# Placeholder macro written by tools/chip_assembly/macros.py
# kind: tile; as ot_pdie_tile_io without die-level pins: an M1-M7 blockage
VERSION 5.7 ;
BUSBITCHARS "[]" ;
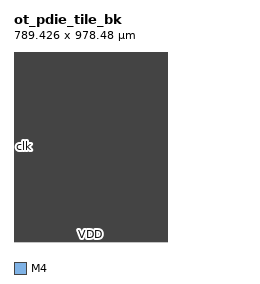
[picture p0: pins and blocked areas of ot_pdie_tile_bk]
MACRO ot_pdie_tile_bk
  FOREIGN ot_pdie_tile_bk 0 0 ;
  SYMMETRY X Y R90 ;
  SIZE 789.426 BY 978.480 ;
  CLASS BLOCK ;
  PIN clk
    DIRECTION INPUT ;
    USE SIGNAL ;
    SHAPE ABUTMENT ;
    PORT
      LAYER M4 ;
      RECT 0.000 489.264 0.192 489.288 ;
    END
  END clk
  PIN VSS
    DIRECTION INOUT ;
    USE GROUND ;
    PORT
      LAYER M4 ;
      RECT 0.492 1.200 788.934 1.296 ;
      RECT 0.492 3.600 788.934 3.696 ;
      RECT 0.492 6.000 788.934 6.096 ;
      RECT 0.492 8.400 788.934 8.496 ;
      RECT 0.492 10.800 788.934 10.896 ;
      RECT 0.492 13.200 788.934 13.296 ;
      RECT 0.492 15.600 788.934 15.696 ;
      RECT 0.492 18.000 788.934 18.096 ;
      RECT 0.492 20.400 788.934 20.496 ;
      RECT 0.492 22.800 788.934 22.896 ;
      RECT 0.492 25.200 788.934 25.296 ;
      RECT 0.492 27.600 788.934 27.696 ;
      RECT 0.492 30.000 788.934 30.096 ;
      RECT 0.492 32.400 788.934 32.496 ;
      RECT 0.492 34.800 788.934 34.896 ;
      RECT 0.492 37.200 788.934 37.296 ;
      RECT 0.492 39.600 788.934 39.696 ;
      RECT 0.492 42.000 788.934 42.096 ;
      RECT 0.492 44.400 788.934 44.496 ;
      RECT 0.492 46.800 788.934 46.896 ;
      RECT 0.492 49.200 788.934 49.296 ;
      RECT 0.492 51.600 788.934 51.696 ;
      RECT 0.492 54.000 788.934 54.096 ;
      RECT 0.492 56.400 788.934 56.496 ;
      RECT 0.492 58.800 788.934 58.896 ;
      RECT 0.492 61.200 788.934 61.296 ;
      RECT 0.492 63.600 788.934 63.696 ;
      RECT 0.492 66.000 788.934 66.096 ;
      RECT 0.492 68.400 788.934 68.496 ;
      RECT 0.492 70.800 788.934 70.896 ;
      RECT 0.492 73.200 788.934 73.296 ;
      RECT 0.492 75.600 788.934 75.696 ;
      RECT 0.492 78.000 788.934 78.096 ;
      RECT 0.492 80.400 788.934 80.496 ;
      RECT 0.492 82.800 788.934 82.896 ;
      RECT 0.492 85.200 788.934 85.296 ;
      RECT 0.492 87.600 788.934 87.696 ;
      RECT 0.492 90.000 788.934 90.096 ;
      RECT 0.492 92.400 788.934 92.496 ;
      RECT 0.492 94.800 788.934 94.896 ;
      RECT 0.492 97.200 788.934 97.296 ;
      RECT 0.492 99.600 788.934 99.696 ;
      RECT 0.492 102.000 788.934 102.096 ;
      RECT 0.492 104.400 788.934 104.496 ;
      RECT 0.492 106.800 788.934 106.896 ;
      RECT 0.492 109.200 788.934 109.296 ;
      RECT 0.492 111.600 788.934 111.696 ;
      RECT 0.492 114.000 788.934 114.096 ;
      RECT 0.492 116.400 788.934 116.496 ;
      RECT 0.492 118.800 788.934 118.896 ;
      RECT 0.492 121.200 788.934 121.296 ;
      RECT 0.492 123.600 788.934 123.696 ;
      RECT 0.492 126.000 788.934 126.096 ;
      RECT 0.492 128.400 788.934 128.496 ;
      RECT 0.492 130.800 788.934 130.896 ;
      RECT 0.492 133.200 788.934 133.296 ;
      RECT 0.492 135.600 788.934 135.696 ;
      RECT 0.492 138.000 788.934 138.096 ;
      RECT 0.492 140.400 788.934 140.496 ;
      RECT 0.492 142.800 788.934 142.896 ;
      RECT 0.492 145.200 788.934 145.296 ;
      RECT 0.492 147.600 788.934 147.696 ;
      RECT 0.492 150.000 788.934 150.096 ;
      RECT 0.492 152.400 788.934 152.496 ;
      RECT 0.492 154.800 788.934 154.896 ;
      RECT 0.492 157.200 788.934 157.296 ;
      RECT 0.492 159.600 788.934 159.696 ;
      RECT 0.492 162.000 788.934 162.096 ;
      RECT 0.492 164.400 788.934 164.496 ;
      RECT 0.492 166.800 788.934 166.896 ;
      RECT 0.492 169.200 788.934 169.296 ;
      RECT 0.492 171.600 788.934 171.696 ;
      RECT 0.492 174.000 788.934 174.096 ;
      RECT 0.492 176.400 788.934 176.496 ;
      RECT 0.492 178.800 788.934 178.896 ;
      RECT 0.492 181.200 788.934 181.296 ;
      RECT 0.492 183.600 788.934 183.696 ;
      RECT 0.492 186.000 788.934 186.096 ;
      RECT 0.492 188.400 788.934 188.496 ;
      RECT 0.492 190.800 788.934 190.896 ;
      RECT 0.492 193.200 788.934 193.296 ;
      RECT 0.492 195.600 788.934 195.696 ;
      RECT 0.492 198.000 788.934 198.096 ;
      RECT 0.492 200.400 788.934 200.496 ;
      RECT 0.492 202.800 788.934 202.896 ;
      RECT 0.492 205.200 788.934 205.296 ;
      RECT 0.492 207.600 788.934 207.696 ;
      RECT 0.492 210.000 788.934 210.096 ;
      RECT 0.492 212.400 788.934 212.496 ;
      RECT 0.492 214.800 788.934 214.896 ;
      RECT 0.492 217.200 788.934 217.296 ;
      RECT 0.492 219.600 788.934 219.696 ;
      RECT 0.492 222.000 788.934 222.096 ;
      RECT 0.492 224.400 788.934 224.496 ;
      RECT 0.492 226.800 788.934 226.896 ;
      RECT 0.492 229.200 788.934 229.296 ;
      RECT 0.492 231.600 788.934 231.696 ;
      RECT 0.492 234.000 788.934 234.096 ;
      RECT 0.492 236.400 788.934 236.496 ;
      RECT 0.492 238.800 788.934 238.896 ;
      RECT 0.492 241.200 788.934 241.296 ;
      RECT 0.492 243.600 788.934 243.696 ;
      RECT 0.492 246.000 788.934 246.096 ;
      RECT 0.492 248.400 788.934 248.496 ;
      RECT 0.492 250.800 788.934 250.896 ;
      RECT 0.492 253.200 788.934 253.296 ;
      RECT 0.492 255.600 788.934 255.696 ;
      RECT 0.492 258.000 788.934 258.096 ;
      RECT 0.492 260.400 788.934 260.496 ;
      RECT 0.492 262.800 788.934 262.896 ;
      RECT 0.492 265.200 788.934 265.296 ;
      RECT 0.492 267.600 788.934 267.696 ;
      RECT 0.492 270.000 788.934 270.096 ;
      RECT 0.492 272.400 788.934 272.496 ;
      RECT 0.492 274.800 788.934 274.896 ;
      RECT 0.492 277.200 788.934 277.296 ;
      RECT 0.492 279.600 788.934 279.696 ;
      RECT 0.492 282.000 788.934 282.096 ;
      RECT 0.492 284.400 788.934 284.496 ;
      RECT 0.492 286.800 788.934 286.896 ;
      RECT 0.492 289.200 788.934 289.296 ;
      RECT 0.492 291.600 788.934 291.696 ;
      RECT 0.492 294.000 788.934 294.096 ;
      RECT 0.492 296.400 788.934 296.496 ;
      RECT 0.492 298.800 788.934 298.896 ;
      RECT 0.492 301.200 788.934 301.296 ;
      RECT 0.492 303.600 788.934 303.696 ;
      RECT 0.492 306.000 788.934 306.096 ;
      RECT 0.492 308.400 788.934 308.496 ;
      RECT 0.492 310.800 788.934 310.896 ;
      RECT 0.492 313.200 788.934 313.296 ;
      RECT 0.492 315.600 788.934 315.696 ;
      RECT 0.492 318.000 788.934 318.096 ;
      RECT 0.492 320.400 788.934 320.496 ;
      RECT 0.492 322.800 788.934 322.896 ;
      RECT 0.492 325.200 788.934 325.296 ;
      RECT 0.492 327.600 788.934 327.696 ;
      RECT 0.492 330.000 788.934 330.096 ;
      RECT 0.492 332.400 788.934 332.496 ;
      RECT 0.492 334.800 788.934 334.896 ;
      RECT 0.492 337.200 788.934 337.296 ;
      RECT 0.492 339.600 788.934 339.696 ;
      RECT 0.492 342.000 788.934 342.096 ;
      RECT 0.492 344.400 788.934 344.496 ;
      RECT 0.492 346.800 788.934 346.896 ;
      RECT 0.492 349.200 788.934 349.296 ;
      RECT 0.492 351.600 788.934 351.696 ;
      RECT 0.492 354.000 788.934 354.096 ;
      RECT 0.492 356.400 788.934 356.496 ;
      RECT 0.492 358.800 788.934 358.896 ;
      RECT 0.492 361.200 788.934 361.296 ;
      RECT 0.492 363.600 788.934 363.696 ;
      RECT 0.492 366.000 788.934 366.096 ;
      RECT 0.492 368.400 788.934 368.496 ;
      RECT 0.492 370.800 788.934 370.896 ;
      RECT 0.492 373.200 788.934 373.296 ;
      RECT 0.492 375.600 788.934 375.696 ;
      RECT 0.492 378.000 788.934 378.096 ;
      RECT 0.492 380.400 788.934 380.496 ;
      RECT 0.492 382.800 788.934 382.896 ;
      RECT 0.492 385.200 788.934 385.296 ;
      RECT 0.492 387.600 788.934 387.696 ;
      RECT 0.492 390.000 788.934 390.096 ;
      RECT 0.492 392.400 788.934 392.496 ;
      RECT 0.492 394.800 788.934 394.896 ;
      RECT 0.492 397.200 788.934 397.296 ;
      RECT 0.492 399.600 788.934 399.696 ;
      RECT 0.492 402.000 788.934 402.096 ;
      RECT 0.492 404.400 788.934 404.496 ;
      RECT 0.492 406.800 788.934 406.896 ;
      RECT 0.492 409.200 788.934 409.296 ;
      RECT 0.492 411.600 788.934 411.696 ;
      RECT 0.492 414.000 788.934 414.096 ;
      RECT 0.492 416.400 788.934 416.496 ;
      RECT 0.492 418.800 788.934 418.896 ;
      RECT 0.492 421.200 788.934 421.296 ;
      RECT 0.492 423.600 788.934 423.696 ;
      RECT 0.492 426.000 788.934 426.096 ;
      RECT 0.492 428.400 788.934 428.496 ;
      RECT 0.492 430.800 788.934 430.896 ;
      RECT 0.492 433.200 788.934 433.296 ;
      RECT 0.492 435.600 788.934 435.696 ;
      RECT 0.492 438.000 788.934 438.096 ;
      RECT 0.492 440.400 788.934 440.496 ;
      RECT 0.492 442.800 788.934 442.896 ;
      RECT 0.492 445.200 788.934 445.296 ;
      RECT 0.492 447.600 788.934 447.696 ;
      RECT 0.492 450.000 788.934 450.096 ;
      RECT 0.492 452.400 788.934 452.496 ;
      RECT 0.492 454.800 788.934 454.896 ;
      RECT 0.492 457.200 788.934 457.296 ;
      RECT 0.492 459.600 788.934 459.696 ;
      RECT 0.492 462.000 788.934 462.096 ;
      RECT 0.492 464.400 788.934 464.496 ;
      RECT 0.492 466.800 788.934 466.896 ;
      RECT 0.492 469.200 788.934 469.296 ;
      RECT 0.492 471.600 788.934 471.696 ;
      RECT 0.492 474.000 788.934 474.096 ;
      RECT 0.492 476.400 788.934 476.496 ;
      RECT 0.492 478.800 788.934 478.896 ;
      RECT 0.492 481.200 788.934 481.296 ;
      RECT 0.492 483.600 788.934 483.696 ;
      RECT 0.492 486.000 788.934 486.096 ;
      RECT 0.492 488.400 788.934 488.496 ;
      RECT 0.492 490.800 788.934 490.896 ;
      RECT 0.492 493.200 788.934 493.296 ;
      RECT 0.492 495.600 788.934 495.696 ;
      RECT 0.492 498.000 788.934 498.096 ;
      RECT 0.492 500.400 788.934 500.496 ;
      RECT 0.492 502.800 788.934 502.896 ;
      RECT 0.492 505.200 788.934 505.296 ;
      RECT 0.492 507.600 788.934 507.696 ;
      RECT 0.492 510.000 788.934 510.096 ;
      RECT 0.492 512.400 788.934 512.496 ;
      RECT 0.492 514.800 788.934 514.896 ;
      RECT 0.492 517.200 788.934 517.296 ;
      RECT 0.492 519.600 788.934 519.696 ;
      RECT 0.492 522.000 788.934 522.096 ;
      RECT 0.492 524.400 788.934 524.496 ;
      RECT 0.492 526.800 788.934 526.896 ;
      RECT 0.492 529.200 788.934 529.296 ;
      RECT 0.492 531.600 788.934 531.696 ;
      RECT 0.492 534.000 788.934 534.096 ;
      RECT 0.492 536.400 788.934 536.496 ;
      RECT 0.492 538.800 788.934 538.896 ;
      RECT 0.492 541.200 788.934 541.296 ;
      RECT 0.492 543.600 788.934 543.696 ;
      RECT 0.492 546.000 788.934 546.096 ;
      RECT 0.492 548.400 788.934 548.496 ;
      RECT 0.492 550.800 788.934 550.896 ;
      RECT 0.492 553.200 788.934 553.296 ;
      RECT 0.492 555.600 788.934 555.696 ;
      RECT 0.492 558.000 788.934 558.096 ;
      RECT 0.492 560.400 788.934 560.496 ;
      RECT 0.492 562.800 788.934 562.896 ;
      RECT 0.492 565.200 788.934 565.296 ;
      RECT 0.492 567.600 788.934 567.696 ;
      RECT 0.492 570.000 788.934 570.096 ;
      RECT 0.492 572.400 788.934 572.496 ;
      RECT 0.492 574.800 788.934 574.896 ;
      RECT 0.492 577.200 788.934 577.296 ;
      RECT 0.492 579.600 788.934 579.696 ;
      RECT 0.492 582.000 788.934 582.096 ;
      RECT 0.492 584.400 788.934 584.496 ;
      RECT 0.492 586.800 788.934 586.896 ;
      RECT 0.492 589.200 788.934 589.296 ;
      RECT 0.492 591.600 788.934 591.696 ;
      RECT 0.492 594.000 788.934 594.096 ;
      RECT 0.492 596.400 788.934 596.496 ;
      RECT 0.492 598.800 788.934 598.896 ;
      RECT 0.492 601.200 788.934 601.296 ;
      RECT 0.492 603.600 788.934 603.696 ;
      RECT 0.492 606.000 788.934 606.096 ;
      RECT 0.492 608.400 788.934 608.496 ;
      RECT 0.492 610.800 788.934 610.896 ;
      RECT 0.492 613.200 788.934 613.296 ;
      RECT 0.492 615.600 788.934 615.696 ;
      RECT 0.492 618.000 788.934 618.096 ;
      RECT 0.492 620.400 788.934 620.496 ;
      RECT 0.492 622.800 788.934 622.896 ;
      RECT 0.492 625.200 788.934 625.296 ;
      RECT 0.492 627.600 788.934 627.696 ;
      RECT 0.492 630.000 788.934 630.096 ;
      RECT 0.492 632.400 788.934 632.496 ;
      RECT 0.492 634.800 788.934 634.896 ;
      RECT 0.492 637.200 788.934 637.296 ;
      RECT 0.492 639.600 788.934 639.696 ;
      RECT 0.492 642.000 788.934 642.096 ;
      RECT 0.492 644.400 788.934 644.496 ;
      RECT 0.492 646.800 788.934 646.896 ;
      RECT 0.492 649.200 788.934 649.296 ;
      RECT 0.492 651.600 788.934 651.696 ;
      RECT 0.492 654.000 788.934 654.096 ;
      RECT 0.492 656.400 788.934 656.496 ;
      RECT 0.492 658.800 788.934 658.896 ;
      RECT 0.492 661.200 788.934 661.296 ;
      RECT 0.492 663.600 788.934 663.696 ;
      RECT 0.492 666.000 788.934 666.096 ;
      RECT 0.492 668.400 788.934 668.496 ;
      RECT 0.492 670.800 788.934 670.896 ;
      RECT 0.492 673.200 788.934 673.296 ;
      RECT 0.492 675.600 788.934 675.696 ;
      RECT 0.492 678.000 788.934 678.096 ;
      RECT 0.492 680.400 788.934 680.496 ;
      RECT 0.492 682.800 788.934 682.896 ;
      RECT 0.492 685.200 788.934 685.296 ;
      RECT 0.492 687.600 788.934 687.696 ;
      RECT 0.492 690.000 788.934 690.096 ;
      RECT 0.492 692.400 788.934 692.496 ;
      RECT 0.492 694.800 788.934 694.896 ;
      RECT 0.492 697.200 788.934 697.296 ;
      RECT 0.492 699.600 788.934 699.696 ;
      RECT 0.492 702.000 788.934 702.096 ;
      RECT 0.492 704.400 788.934 704.496 ;
      RECT 0.492 706.800 788.934 706.896 ;
      RECT 0.492 709.200 788.934 709.296 ;
      RECT 0.492 711.600 788.934 711.696 ;
      RECT 0.492 714.000 788.934 714.096 ;
      RECT 0.492 716.400 788.934 716.496 ;
      RECT 0.492 718.800 788.934 718.896 ;
      RECT 0.492 721.200 788.934 721.296 ;
      RECT 0.492 723.600 788.934 723.696 ;
      RECT 0.492 726.000 788.934 726.096 ;
      RECT 0.492 728.400 788.934 728.496 ;
      RECT 0.492 730.800 788.934 730.896 ;
      RECT 0.492 733.200 788.934 733.296 ;
      RECT 0.492 735.600 788.934 735.696 ;
      RECT 0.492 738.000 788.934 738.096 ;
      RECT 0.492 740.400 788.934 740.496 ;
      RECT 0.492 742.800 788.934 742.896 ;
      RECT 0.492 745.200 788.934 745.296 ;
      RECT 0.492 747.600 788.934 747.696 ;
      RECT 0.492 750.000 788.934 750.096 ;
      RECT 0.492 752.400 788.934 752.496 ;
      RECT 0.492 754.800 788.934 754.896 ;
      RECT 0.492 757.200 788.934 757.296 ;
      RECT 0.492 759.600 788.934 759.696 ;
      RECT 0.492 762.000 788.934 762.096 ;
      RECT 0.492 764.400 788.934 764.496 ;
      RECT 0.492 766.800 788.934 766.896 ;
      RECT 0.492 769.200 788.934 769.296 ;
      RECT 0.492 771.600 788.934 771.696 ;
      RECT 0.492 774.000 788.934 774.096 ;
      RECT 0.492 776.400 788.934 776.496 ;
      RECT 0.492 778.800 788.934 778.896 ;
      RECT 0.492 781.200 788.934 781.296 ;
      RECT 0.492 783.600 788.934 783.696 ;
      RECT 0.492 786.000 788.934 786.096 ;
      RECT 0.492 788.400 788.934 788.496 ;
      RECT 0.492 790.800 788.934 790.896 ;
      RECT 0.492 793.200 788.934 793.296 ;
      RECT 0.492 795.600 788.934 795.696 ;
      RECT 0.492 798.000 788.934 798.096 ;
      RECT 0.492 800.400 788.934 800.496 ;
      RECT 0.492 802.800 788.934 802.896 ;
      RECT 0.492 805.200 788.934 805.296 ;
      RECT 0.492 807.600 788.934 807.696 ;
      RECT 0.492 810.000 788.934 810.096 ;
      RECT 0.492 812.400 788.934 812.496 ;
      RECT 0.492 814.800 788.934 814.896 ;
      RECT 0.492 817.200 788.934 817.296 ;
      RECT 0.492 819.600 788.934 819.696 ;
      RECT 0.492 822.000 788.934 822.096 ;
      RECT 0.492 824.400 788.934 824.496 ;
      RECT 0.492 826.800 788.934 826.896 ;
      RECT 0.492 829.200 788.934 829.296 ;
      RECT 0.492 831.600 788.934 831.696 ;
      RECT 0.492 834.000 788.934 834.096 ;
      RECT 0.492 836.400 788.934 836.496 ;
      RECT 0.492 838.800 788.934 838.896 ;
      RECT 0.492 841.200 788.934 841.296 ;
      RECT 0.492 843.600 788.934 843.696 ;
      RECT 0.492 846.000 788.934 846.096 ;
      RECT 0.492 848.400 788.934 848.496 ;
      RECT 0.492 850.800 788.934 850.896 ;
      RECT 0.492 853.200 788.934 853.296 ;
      RECT 0.492 855.600 788.934 855.696 ;
      RECT 0.492 858.000 788.934 858.096 ;
      RECT 0.492 860.400 788.934 860.496 ;
      RECT 0.492 862.800 788.934 862.896 ;
      RECT 0.492 865.200 788.934 865.296 ;
      RECT 0.492 867.600 788.934 867.696 ;
      RECT 0.492 870.000 788.934 870.096 ;
      RECT 0.492 872.400 788.934 872.496 ;
      RECT 0.492 874.800 788.934 874.896 ;
      RECT 0.492 877.200 788.934 877.296 ;
      RECT 0.492 879.600 788.934 879.696 ;
      RECT 0.492 882.000 788.934 882.096 ;
      RECT 0.492 884.400 788.934 884.496 ;
      RECT 0.492 886.800 788.934 886.896 ;
      RECT 0.492 889.200 788.934 889.296 ;
      RECT 0.492 891.600 788.934 891.696 ;
      RECT 0.492 894.000 788.934 894.096 ;
      RECT 0.492 896.400 788.934 896.496 ;
      RECT 0.492 898.800 788.934 898.896 ;
      RECT 0.492 901.200 788.934 901.296 ;
      RECT 0.492 903.600 788.934 903.696 ;
      RECT 0.492 906.000 788.934 906.096 ;
      RECT 0.492 908.400 788.934 908.496 ;
      RECT 0.492 910.800 788.934 910.896 ;
      RECT 0.492 913.200 788.934 913.296 ;
      RECT 0.492 915.600 788.934 915.696 ;
      RECT 0.492 918.000 788.934 918.096 ;
      RECT 0.492 920.400 788.934 920.496 ;
      RECT 0.492 922.800 788.934 922.896 ;
      RECT 0.492 925.200 788.934 925.296 ;
      RECT 0.492 927.600 788.934 927.696 ;
      RECT 0.492 930.000 788.934 930.096 ;
      RECT 0.492 932.400 788.934 932.496 ;
      RECT 0.492 934.800 788.934 934.896 ;
      RECT 0.492 937.200 788.934 937.296 ;
      RECT 0.492 939.600 788.934 939.696 ;
      RECT 0.492 942.000 788.934 942.096 ;
      RECT 0.492 944.400 788.934 944.496 ;
      RECT 0.492 946.800 788.934 946.896 ;
      RECT 0.492 949.200 788.934 949.296 ;
      RECT 0.492 951.600 788.934 951.696 ;
      RECT 0.492 954.000 788.934 954.096 ;
      RECT 0.492 956.400 788.934 956.496 ;
      RECT 0.492 958.800 788.934 958.896 ;
      RECT 0.492 961.200 788.934 961.296 ;
      RECT 0.492 963.600 788.934 963.696 ;
      RECT 0.492 966.000 788.934 966.096 ;
      RECT 0.492 968.400 788.934 968.496 ;
      RECT 0.492 970.800 788.934 970.896 ;
      RECT 0.492 973.200 788.934 973.296 ;
      RECT 0.492 975.600 788.934 975.696 ;
    END
  END VSS
  PIN VDD
    DIRECTION INOUT ;
    USE POWER ;
    PORT
      LAYER M4 ;
      RECT 0.492 2.400 788.934 2.496 ;
      RECT 0.492 4.800 788.934 4.896 ;
      RECT 0.492 7.200 788.934 7.296 ;
      RECT 0.492 9.600 788.934 9.696 ;
      RECT 0.492 12.000 788.934 12.096 ;
      RECT 0.492 14.400 788.934 14.496 ;
      RECT 0.492 16.800 788.934 16.896 ;
      RECT 0.492 19.200 788.934 19.296 ;
      RECT 0.492 21.600 788.934 21.696 ;
      RECT 0.492 24.000 788.934 24.096 ;
      RECT 0.492 26.400 788.934 26.496 ;
      RECT 0.492 28.800 788.934 28.896 ;
      RECT 0.492 31.200 788.934 31.296 ;
      RECT 0.492 33.600 788.934 33.696 ;
      RECT 0.492 36.000 788.934 36.096 ;
      RECT 0.492 38.400 788.934 38.496 ;
      RECT 0.492 40.800 788.934 40.896 ;
      RECT 0.492 43.200 788.934 43.296 ;
      RECT 0.492 45.600 788.934 45.696 ;
      RECT 0.492 48.000 788.934 48.096 ;
      RECT 0.492 50.400 788.934 50.496 ;
      RECT 0.492 52.800 788.934 52.896 ;
      RECT 0.492 55.200 788.934 55.296 ;
      RECT 0.492 57.600 788.934 57.696 ;
      RECT 0.492 60.000 788.934 60.096 ;
      RECT 0.492 62.400 788.934 62.496 ;
      RECT 0.492 64.800 788.934 64.896 ;
      RECT 0.492 67.200 788.934 67.296 ;
      RECT 0.492 69.600 788.934 69.696 ;
      RECT 0.492 72.000 788.934 72.096 ;
      RECT 0.492 74.400 788.934 74.496 ;
      RECT 0.492 76.800 788.934 76.896 ;
      RECT 0.492 79.200 788.934 79.296 ;
      RECT 0.492 81.600 788.934 81.696 ;
      RECT 0.492 84.000 788.934 84.096 ;
      RECT 0.492 86.400 788.934 86.496 ;
      RECT 0.492 88.800 788.934 88.896 ;
      RECT 0.492 91.200 788.934 91.296 ;
      RECT 0.492 93.600 788.934 93.696 ;
      RECT 0.492 96.000 788.934 96.096 ;
      RECT 0.492 98.400 788.934 98.496 ;
      RECT 0.492 100.800 788.934 100.896 ;
      RECT 0.492 103.200 788.934 103.296 ;
      RECT 0.492 105.600 788.934 105.696 ;
      RECT 0.492 108.000 788.934 108.096 ;
      RECT 0.492 110.400 788.934 110.496 ;
      RECT 0.492 112.800 788.934 112.896 ;
      RECT 0.492 115.200 788.934 115.296 ;
      RECT 0.492 117.600 788.934 117.696 ;
      RECT 0.492 120.000 788.934 120.096 ;
      RECT 0.492 122.400 788.934 122.496 ;
      RECT 0.492 124.800 788.934 124.896 ;
      RECT 0.492 127.200 788.934 127.296 ;
      RECT 0.492 129.600 788.934 129.696 ;
      RECT 0.492 132.000 788.934 132.096 ;
      RECT 0.492 134.400 788.934 134.496 ;
      RECT 0.492 136.800 788.934 136.896 ;
      RECT 0.492 139.200 788.934 139.296 ;
      RECT 0.492 141.600 788.934 141.696 ;
      RECT 0.492 144.000 788.934 144.096 ;
      RECT 0.492 146.400 788.934 146.496 ;
      RECT 0.492 148.800 788.934 148.896 ;
      RECT 0.492 151.200 788.934 151.296 ;
      RECT 0.492 153.600 788.934 153.696 ;
      RECT 0.492 156.000 788.934 156.096 ;
      RECT 0.492 158.400 788.934 158.496 ;
      RECT 0.492 160.800 788.934 160.896 ;
      RECT 0.492 163.200 788.934 163.296 ;
      RECT 0.492 165.600 788.934 165.696 ;
      RECT 0.492 168.000 788.934 168.096 ;
      RECT 0.492 170.400 788.934 170.496 ;
      RECT 0.492 172.800 788.934 172.896 ;
      RECT 0.492 175.200 788.934 175.296 ;
      RECT 0.492 177.600 788.934 177.696 ;
      RECT 0.492 180.000 788.934 180.096 ;
      RECT 0.492 182.400 788.934 182.496 ;
      RECT 0.492 184.800 788.934 184.896 ;
      RECT 0.492 187.200 788.934 187.296 ;
      RECT 0.492 189.600 788.934 189.696 ;
      RECT 0.492 192.000 788.934 192.096 ;
      RECT 0.492 194.400 788.934 194.496 ;
      RECT 0.492 196.800 788.934 196.896 ;
      RECT 0.492 199.200 788.934 199.296 ;
      RECT 0.492 201.600 788.934 201.696 ;
      RECT 0.492 204.000 788.934 204.096 ;
      RECT 0.492 206.400 788.934 206.496 ;
      RECT 0.492 208.800 788.934 208.896 ;
      RECT 0.492 211.200 788.934 211.296 ;
      RECT 0.492 213.600 788.934 213.696 ;
      RECT 0.492 216.000 788.934 216.096 ;
      RECT 0.492 218.400 788.934 218.496 ;
      RECT 0.492 220.800 788.934 220.896 ;
      RECT 0.492 223.200 788.934 223.296 ;
      RECT 0.492 225.600 788.934 225.696 ;
      RECT 0.492 228.000 788.934 228.096 ;
      RECT 0.492 230.400 788.934 230.496 ;
      RECT 0.492 232.800 788.934 232.896 ;
      RECT 0.492 235.200 788.934 235.296 ;
      RECT 0.492 237.600 788.934 237.696 ;
      RECT 0.492 240.000 788.934 240.096 ;
      RECT 0.492 242.400 788.934 242.496 ;
      RECT 0.492 244.800 788.934 244.896 ;
      RECT 0.492 247.200 788.934 247.296 ;
      RECT 0.492 249.600 788.934 249.696 ;
      RECT 0.492 252.000 788.934 252.096 ;
      RECT 0.492 254.400 788.934 254.496 ;
      RECT 0.492 256.800 788.934 256.896 ;
      RECT 0.492 259.200 788.934 259.296 ;
      RECT 0.492 261.600 788.934 261.696 ;
      RECT 0.492 264.000 788.934 264.096 ;
      RECT 0.492 266.400 788.934 266.496 ;
      RECT 0.492 268.800 788.934 268.896 ;
      RECT 0.492 271.200 788.934 271.296 ;
      RECT 0.492 273.600 788.934 273.696 ;
      RECT 0.492 276.000 788.934 276.096 ;
      RECT 0.492 278.400 788.934 278.496 ;
      RECT 0.492 280.800 788.934 280.896 ;
      RECT 0.492 283.200 788.934 283.296 ;
      RECT 0.492 285.600 788.934 285.696 ;
      RECT 0.492 288.000 788.934 288.096 ;
      RECT 0.492 290.400 788.934 290.496 ;
      RECT 0.492 292.800 788.934 292.896 ;
      RECT 0.492 295.200 788.934 295.296 ;
      RECT 0.492 297.600 788.934 297.696 ;
      RECT 0.492 300.000 788.934 300.096 ;
      RECT 0.492 302.400 788.934 302.496 ;
      RECT 0.492 304.800 788.934 304.896 ;
      RECT 0.492 307.200 788.934 307.296 ;
      RECT 0.492 309.600 788.934 309.696 ;
      RECT 0.492 312.000 788.934 312.096 ;
      RECT 0.492 314.400 788.934 314.496 ;
      RECT 0.492 316.800 788.934 316.896 ;
      RECT 0.492 319.200 788.934 319.296 ;
      RECT 0.492 321.600 788.934 321.696 ;
      RECT 0.492 324.000 788.934 324.096 ;
      RECT 0.492 326.400 788.934 326.496 ;
      RECT 0.492 328.800 788.934 328.896 ;
      RECT 0.492 331.200 788.934 331.296 ;
      RECT 0.492 333.600 788.934 333.696 ;
      RECT 0.492 336.000 788.934 336.096 ;
      RECT 0.492 338.400 788.934 338.496 ;
      RECT 0.492 340.800 788.934 340.896 ;
      RECT 0.492 343.200 788.934 343.296 ;
      RECT 0.492 345.600 788.934 345.696 ;
      RECT 0.492 348.000 788.934 348.096 ;
      RECT 0.492 350.400 788.934 350.496 ;
      RECT 0.492 352.800 788.934 352.896 ;
      RECT 0.492 355.200 788.934 355.296 ;
      RECT 0.492 357.600 788.934 357.696 ;
      RECT 0.492 360.000 788.934 360.096 ;
      RECT 0.492 362.400 788.934 362.496 ;
      RECT 0.492 364.800 788.934 364.896 ;
      RECT 0.492 367.200 788.934 367.296 ;
      RECT 0.492 369.600 788.934 369.696 ;
      RECT 0.492 372.000 788.934 372.096 ;
      RECT 0.492 374.400 788.934 374.496 ;
      RECT 0.492 376.800 788.934 376.896 ;
      RECT 0.492 379.200 788.934 379.296 ;
      RECT 0.492 381.600 788.934 381.696 ;
      RECT 0.492 384.000 788.934 384.096 ;
      RECT 0.492 386.400 788.934 386.496 ;
      RECT 0.492 388.800 788.934 388.896 ;
      RECT 0.492 391.200 788.934 391.296 ;
      RECT 0.492 393.600 788.934 393.696 ;
      RECT 0.492 396.000 788.934 396.096 ;
      RECT 0.492 398.400 788.934 398.496 ;
      RECT 0.492 400.800 788.934 400.896 ;
      RECT 0.492 403.200 788.934 403.296 ;
      RECT 0.492 405.600 788.934 405.696 ;
      RECT 0.492 408.000 788.934 408.096 ;
      RECT 0.492 410.400 788.934 410.496 ;
      RECT 0.492 412.800 788.934 412.896 ;
      RECT 0.492 415.200 788.934 415.296 ;
      RECT 0.492 417.600 788.934 417.696 ;
      RECT 0.492 420.000 788.934 420.096 ;
      RECT 0.492 422.400 788.934 422.496 ;
      RECT 0.492 424.800 788.934 424.896 ;
      RECT 0.492 427.200 788.934 427.296 ;
      RECT 0.492 429.600 788.934 429.696 ;
      RECT 0.492 432.000 788.934 432.096 ;
      RECT 0.492 434.400 788.934 434.496 ;
      RECT 0.492 436.800 788.934 436.896 ;
      RECT 0.492 439.200 788.934 439.296 ;
      RECT 0.492 441.600 788.934 441.696 ;
      RECT 0.492 444.000 788.934 444.096 ;
      RECT 0.492 446.400 788.934 446.496 ;
      RECT 0.492 448.800 788.934 448.896 ;
      RECT 0.492 451.200 788.934 451.296 ;
      RECT 0.492 453.600 788.934 453.696 ;
      RECT 0.492 456.000 788.934 456.096 ;
      RECT 0.492 458.400 788.934 458.496 ;
      RECT 0.492 460.800 788.934 460.896 ;
      RECT 0.492 463.200 788.934 463.296 ;
      RECT 0.492 465.600 788.934 465.696 ;
      RECT 0.492 468.000 788.934 468.096 ;
      RECT 0.492 470.400 788.934 470.496 ;
      RECT 0.492 472.800 788.934 472.896 ;
      RECT 0.492 475.200 788.934 475.296 ;
      RECT 0.492 477.600 788.934 477.696 ;
      RECT 0.492 480.000 788.934 480.096 ;
      RECT 0.492 482.400 788.934 482.496 ;
      RECT 0.492 484.800 788.934 484.896 ;
      RECT 0.492 487.200 788.934 487.296 ;
      RECT 0.492 489.600 788.934 489.696 ;
      RECT 0.492 492.000 788.934 492.096 ;
      RECT 0.492 494.400 788.934 494.496 ;
      RECT 0.492 496.800 788.934 496.896 ;
      RECT 0.492 499.200 788.934 499.296 ;
      RECT 0.492 501.600 788.934 501.696 ;
      RECT 0.492 504.000 788.934 504.096 ;
      RECT 0.492 506.400 788.934 506.496 ;
      RECT 0.492 508.800 788.934 508.896 ;
      RECT 0.492 511.200 788.934 511.296 ;
      RECT 0.492 513.600 788.934 513.696 ;
      RECT 0.492 516.000 788.934 516.096 ;
      RECT 0.492 518.400 788.934 518.496 ;
      RECT 0.492 520.800 788.934 520.896 ;
      RECT 0.492 523.200 788.934 523.296 ;
      RECT 0.492 525.600 788.934 525.696 ;
      RECT 0.492 528.000 788.934 528.096 ;
      RECT 0.492 530.400 788.934 530.496 ;
      RECT 0.492 532.800 788.934 532.896 ;
      RECT 0.492 535.200 788.934 535.296 ;
      RECT 0.492 537.600 788.934 537.696 ;
      RECT 0.492 540.000 788.934 540.096 ;
      RECT 0.492 542.400 788.934 542.496 ;
      RECT 0.492 544.800 788.934 544.896 ;
      RECT 0.492 547.200 788.934 547.296 ;
      RECT 0.492 549.600 788.934 549.696 ;
      RECT 0.492 552.000 788.934 552.096 ;
      RECT 0.492 554.400 788.934 554.496 ;
      RECT 0.492 556.800 788.934 556.896 ;
      RECT 0.492 559.200 788.934 559.296 ;
      RECT 0.492 561.600 788.934 561.696 ;
      RECT 0.492 564.000 788.934 564.096 ;
      RECT 0.492 566.400 788.934 566.496 ;
      RECT 0.492 568.800 788.934 568.896 ;
      RECT 0.492 571.200 788.934 571.296 ;
      RECT 0.492 573.600 788.934 573.696 ;
      RECT 0.492 576.000 788.934 576.096 ;
      RECT 0.492 578.400 788.934 578.496 ;
      RECT 0.492 580.800 788.934 580.896 ;
      RECT 0.492 583.200 788.934 583.296 ;
      RECT 0.492 585.600 788.934 585.696 ;
      RECT 0.492 588.000 788.934 588.096 ;
      RECT 0.492 590.400 788.934 590.496 ;
      RECT 0.492 592.800 788.934 592.896 ;
      RECT 0.492 595.200 788.934 595.296 ;
      RECT 0.492 597.600 788.934 597.696 ;
      RECT 0.492 600.000 788.934 600.096 ;
      RECT 0.492 602.400 788.934 602.496 ;
      RECT 0.492 604.800 788.934 604.896 ;
      RECT 0.492 607.200 788.934 607.296 ;
      RECT 0.492 609.600 788.934 609.696 ;
      RECT 0.492 612.000 788.934 612.096 ;
      RECT 0.492 614.400 788.934 614.496 ;
      RECT 0.492 616.800 788.934 616.896 ;
      RECT 0.492 619.200 788.934 619.296 ;
      RECT 0.492 621.600 788.934 621.696 ;
      RECT 0.492 624.000 788.934 624.096 ;
      RECT 0.492 626.400 788.934 626.496 ;
      RECT 0.492 628.800 788.934 628.896 ;
      RECT 0.492 631.200 788.934 631.296 ;
      RECT 0.492 633.600 788.934 633.696 ;
      RECT 0.492 636.000 788.934 636.096 ;
      RECT 0.492 638.400 788.934 638.496 ;
      RECT 0.492 640.800 788.934 640.896 ;
      RECT 0.492 643.200 788.934 643.296 ;
      RECT 0.492 645.600 788.934 645.696 ;
      RECT 0.492 648.000 788.934 648.096 ;
      RECT 0.492 650.400 788.934 650.496 ;
      RECT 0.492 652.800 788.934 652.896 ;
      RECT 0.492 655.200 788.934 655.296 ;
      RECT 0.492 657.600 788.934 657.696 ;
      RECT 0.492 660.000 788.934 660.096 ;
      RECT 0.492 662.400 788.934 662.496 ;
      RECT 0.492 664.800 788.934 664.896 ;
      RECT 0.492 667.200 788.934 667.296 ;
      RECT 0.492 669.600 788.934 669.696 ;
      RECT 0.492 672.000 788.934 672.096 ;
      RECT 0.492 674.400 788.934 674.496 ;
      RECT 0.492 676.800 788.934 676.896 ;
      RECT 0.492 679.200 788.934 679.296 ;
      RECT 0.492 681.600 788.934 681.696 ;
      RECT 0.492 684.000 788.934 684.096 ;
      RECT 0.492 686.400 788.934 686.496 ;
      RECT 0.492 688.800 788.934 688.896 ;
      RECT 0.492 691.200 788.934 691.296 ;
      RECT 0.492 693.600 788.934 693.696 ;
      RECT 0.492 696.000 788.934 696.096 ;
      RECT 0.492 698.400 788.934 698.496 ;
      RECT 0.492 700.800 788.934 700.896 ;
      RECT 0.492 703.200 788.934 703.296 ;
      RECT 0.492 705.600 788.934 705.696 ;
      RECT 0.492 708.000 788.934 708.096 ;
      RECT 0.492 710.400 788.934 710.496 ;
      RECT 0.492 712.800 788.934 712.896 ;
      RECT 0.492 715.200 788.934 715.296 ;
      RECT 0.492 717.600 788.934 717.696 ;
      RECT 0.492 720.000 788.934 720.096 ;
      RECT 0.492 722.400 788.934 722.496 ;
      RECT 0.492 724.800 788.934 724.896 ;
      RECT 0.492 727.200 788.934 727.296 ;
      RECT 0.492 729.600 788.934 729.696 ;
      RECT 0.492 732.000 788.934 732.096 ;
      RECT 0.492 734.400 788.934 734.496 ;
      RECT 0.492 736.800 788.934 736.896 ;
      RECT 0.492 739.200 788.934 739.296 ;
      RECT 0.492 741.600 788.934 741.696 ;
      RECT 0.492 744.000 788.934 744.096 ;
      RECT 0.492 746.400 788.934 746.496 ;
      RECT 0.492 748.800 788.934 748.896 ;
      RECT 0.492 751.200 788.934 751.296 ;
      RECT 0.492 753.600 788.934 753.696 ;
      RECT 0.492 756.000 788.934 756.096 ;
      RECT 0.492 758.400 788.934 758.496 ;
      RECT 0.492 760.800 788.934 760.896 ;
      RECT 0.492 763.200 788.934 763.296 ;
      RECT 0.492 765.600 788.934 765.696 ;
      RECT 0.492 768.000 788.934 768.096 ;
      RECT 0.492 770.400 788.934 770.496 ;
      RECT 0.492 772.800 788.934 772.896 ;
      RECT 0.492 775.200 788.934 775.296 ;
      RECT 0.492 777.600 788.934 777.696 ;
      RECT 0.492 780.000 788.934 780.096 ;
      RECT 0.492 782.400 788.934 782.496 ;
      RECT 0.492 784.800 788.934 784.896 ;
      RECT 0.492 787.200 788.934 787.296 ;
      RECT 0.492 789.600 788.934 789.696 ;
      RECT 0.492 792.000 788.934 792.096 ;
      RECT 0.492 794.400 788.934 794.496 ;
      RECT 0.492 796.800 788.934 796.896 ;
      RECT 0.492 799.200 788.934 799.296 ;
      RECT 0.492 801.600 788.934 801.696 ;
      RECT 0.492 804.000 788.934 804.096 ;
      RECT 0.492 806.400 788.934 806.496 ;
      RECT 0.492 808.800 788.934 808.896 ;
      RECT 0.492 811.200 788.934 811.296 ;
      RECT 0.492 813.600 788.934 813.696 ;
      RECT 0.492 816.000 788.934 816.096 ;
      RECT 0.492 818.400 788.934 818.496 ;
      RECT 0.492 820.800 788.934 820.896 ;
      RECT 0.492 823.200 788.934 823.296 ;
      RECT 0.492 825.600 788.934 825.696 ;
      RECT 0.492 828.000 788.934 828.096 ;
      RECT 0.492 830.400 788.934 830.496 ;
      RECT 0.492 832.800 788.934 832.896 ;
      RECT 0.492 835.200 788.934 835.296 ;
      RECT 0.492 837.600 788.934 837.696 ;
      RECT 0.492 840.000 788.934 840.096 ;
      RECT 0.492 842.400 788.934 842.496 ;
      RECT 0.492 844.800 788.934 844.896 ;
      RECT 0.492 847.200 788.934 847.296 ;
      RECT 0.492 849.600 788.934 849.696 ;
      RECT 0.492 852.000 788.934 852.096 ;
      RECT 0.492 854.400 788.934 854.496 ;
      RECT 0.492 856.800 788.934 856.896 ;
      RECT 0.492 859.200 788.934 859.296 ;
      RECT 0.492 861.600 788.934 861.696 ;
      RECT 0.492 864.000 788.934 864.096 ;
      RECT 0.492 866.400 788.934 866.496 ;
      RECT 0.492 868.800 788.934 868.896 ;
      RECT 0.492 871.200 788.934 871.296 ;
      RECT 0.492 873.600 788.934 873.696 ;
      RECT 0.492 876.000 788.934 876.096 ;
      RECT 0.492 878.400 788.934 878.496 ;
      RECT 0.492 880.800 788.934 880.896 ;
      RECT 0.492 883.200 788.934 883.296 ;
      RECT 0.492 885.600 788.934 885.696 ;
      RECT 0.492 888.000 788.934 888.096 ;
      RECT 0.492 890.400 788.934 890.496 ;
      RECT 0.492 892.800 788.934 892.896 ;
      RECT 0.492 895.200 788.934 895.296 ;
      RECT 0.492 897.600 788.934 897.696 ;
      RECT 0.492 900.000 788.934 900.096 ;
      RECT 0.492 902.400 788.934 902.496 ;
      RECT 0.492 904.800 788.934 904.896 ;
      RECT 0.492 907.200 788.934 907.296 ;
      RECT 0.492 909.600 788.934 909.696 ;
      RECT 0.492 912.000 788.934 912.096 ;
      RECT 0.492 914.400 788.934 914.496 ;
      RECT 0.492 916.800 788.934 916.896 ;
      RECT 0.492 919.200 788.934 919.296 ;
      RECT 0.492 921.600 788.934 921.696 ;
      RECT 0.492 924.000 788.934 924.096 ;
      RECT 0.492 926.400 788.934 926.496 ;
      RECT 0.492 928.800 788.934 928.896 ;
      RECT 0.492 931.200 788.934 931.296 ;
      RECT 0.492 933.600 788.934 933.696 ;
      RECT 0.492 936.000 788.934 936.096 ;
      RECT 0.492 938.400 788.934 938.496 ;
      RECT 0.492 940.800 788.934 940.896 ;
      RECT 0.492 943.200 788.934 943.296 ;
      RECT 0.492 945.600 788.934 945.696 ;
      RECT 0.492 948.000 788.934 948.096 ;
      RECT 0.492 950.400 788.934 950.496 ;
      RECT 0.492 952.800 788.934 952.896 ;
      RECT 0.492 955.200 788.934 955.296 ;
      RECT 0.492 957.600 788.934 957.696 ;
      RECT 0.492 960.000 788.934 960.096 ;
      RECT 0.492 962.400 788.934 962.496 ;
      RECT 0.492 964.800 788.934 964.896 ;
      RECT 0.492 967.200 788.934 967.296 ;
      RECT 0.492 969.600 788.934 969.696 ;
      RECT 0.492 972.000 788.934 972.096 ;
      RECT 0.492 974.400 788.934 974.496 ;
      RECT 0.492 976.800 788.934 976.896 ;
    END
  END VDD
  OBS
    LAYER M1 ;
    RECT 0 0 789.426 978.480 ;
    LAYER M2 ;
    RECT 0 0 789.426 978.480 ;
    LAYER M3 ;
    RECT 0 0 789.426 978.480 ;
    LAYER M4 ;
    RECT 0 0 789.426 978.480 ;
    LAYER M5 ;
    RECT 0 0 789.426 978.480 ;
    LAYER M6 ;
    RECT 0 0 789.426 978.480 ;
    LAYER M7 ;
    RECT 0 0 789.426 978.480 ;
  END
END ot_pdie_tile_bk

END LIBRARY
